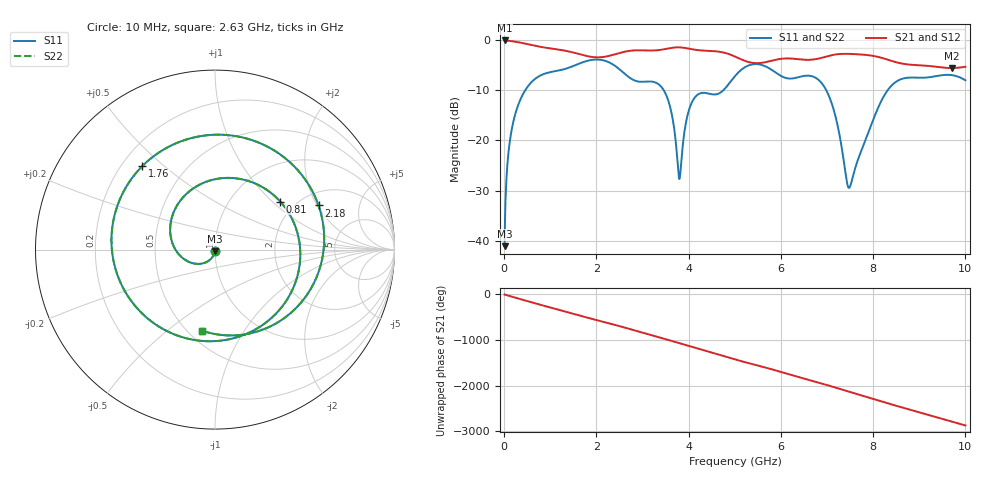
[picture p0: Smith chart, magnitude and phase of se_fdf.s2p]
! Created with skrf (http://scikit-rf.org).
# GHz S RI R 50.0
!freq ReS11 ImS11 ReS21 ImS21 ReS12 ImS12 ReS22 ImS22
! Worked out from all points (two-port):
!   1000 points, 10 MHz to 10 GHz, reference 50 ohm
!   highest |S21| = -0.01 dB at 10 MHz (marker M1); lowest = -5.5 dB at 9.7 GHz (marker M2)
!   |S21| within 3 dB of the highest: start of sweep to 1.74 GHz; 2.31 GHz to 4.95 GHz (2.64 GHz wide, 72.7 % of centre) (the widest 2 of 3)
!   lowest |S11| = -41.1 dB at 10 MHz (marker M3), VSWR 1.02, Z = 49.9 - j0.871 ohm
!   |S11| at or under -10 dB: start of sweep to 454.8 MHz; 3.462 GHz to 4.747 GHz (1.285 GHz wide, 31.3 % of centre); 6.986 GHz to 8.312 GHz (1.326 GHz wide, 17.3 % of centre)
!   |S22| runs from -41.1 to -3.8 dB; largest |S21 - S12| = 3.5e-08
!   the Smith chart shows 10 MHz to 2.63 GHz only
!   S11 on the Smith chart (normalised r, x): 10 MHz: 1.00, -0.02; 810 MHz: 1.67, +1.12; 1.76 GHz: 0.28, +0.42; 2.18 GHz: 2.53, +2.05; 2.63 GHz: 0.58, -0.67
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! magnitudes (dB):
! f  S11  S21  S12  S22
! 10 MHz  -41.1  0.0  0.0  -41.1
! 100 MHz  -21.9  -0.1  -0.1  -21.9
! 220 MHz  -15.5  -0.2  -0.2  -15.5
! 460 MHz  -9.9  -0.6  -0.6  -9.9
! 810 MHz  -6.9  -1.3  -1.3  -6.9
! 1.68 GHz  -4.4  -2.9  -2.9  -4.4
! 1.76 GHz  -4.2  -3.1  -3.1  -4.2
! 2.18 GHz  -4.1  -3.3  -3.3  -4.1
! 2.63 GHz  -6.8  -2.2  -2.2  -6.8
! 3.34 GHz  -8.7  -1.9  -1.9  -8.7
! 3.6 GHz  -13.3  -1.5  -1.5  -13.3
! 3.8 GHz  -27.7  -1.4  -1.4  -27.7
! 3.95 GHz  -16.0  -1.6  -1.6  -16.0
! 4.1 GHz  -11.9  -1.8  -1.8  -11.9
! 5.01 GHz  -7.1  -3.2  -3.2  -7.1
! 5.46 GHz  -4.7  -4.6  -4.6  -4.7
! 6.67 GHz  -7.2  -3.8  -3.8  -7.2
! 7.1 GHz  -12.5  -3.0  -3.0  -12.5
! 7.48 GHz  -29.5  -2.7  -2.7  -29.5
! 8.34 GHz  -9.7  -3.9  -3.9  -9.7
! 9.7 GHz  -6.9  -5.5  -5.5  -6.9
! 10 GHz  -8.0  -5.3  -5.3  -8.0
